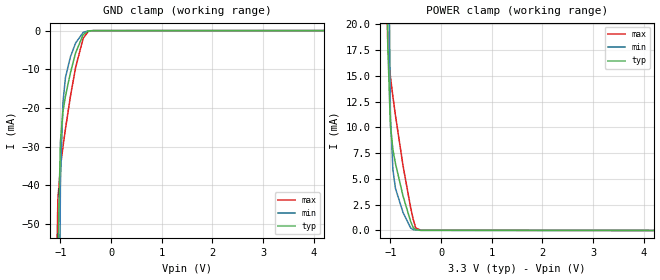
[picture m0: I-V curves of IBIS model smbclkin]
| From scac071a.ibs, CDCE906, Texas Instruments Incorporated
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[Model]   smbclkin
Model_type   Input
Polarity   Non-Inverting
Vinl   =   0.80V
Vinh   =   2.10V
|Variable   typ   min   max
C_comp   1.420e-12   1.379e-12   1.479e-12
|Variable   typ   min   max
[Voltage range]   3.3   3.0   3.6
|Variable   typ   min   max
[Temperature range]  55   110   -15
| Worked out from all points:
|   GND clamp passes 1 mA (typ) near -0.55 V on its own axis
|   POWER clamp passes 1 mA (typ) near -0.61 V on its own axis
| Note: The Input-Buffer model contains a Pull-Up resistor of
|   3.3MOhm(typ) 5MOhm(min) and 2.6MOhm(max).
[GND_clamp]
|Volts   typ   min   max
-1.2V     -6.266A    -10.23A    -3.28A
-1.1V     -212.2mA   -514.8mA   -81.05mA
-1.05V    -58.05mA   -127.1mA   -43.66mA
-1V       -28.77mA   -39.71mA   -35.23mA
-950mV    -20.93mA   -18.55mA   -30.02mA
-900mV    -16.9mA    -12.07mA   -25.35mA
-800mV    -10.78mA   -6.697mA   -16.83mA
-700mV    -5.762mA   -3.218mA   -9.538mA
-550mV    -1.018mA   -463.9uA   -1.988mA
-450mV    -128.8uA   -64.99uA   -225.9uA
-350mV    -10.79uA   -7.496uA   -11.25uA
4.2V      0A         0A         0A
[POWER_clamp]
|Volts   typ   min   max
-1.2V     1.548A     2.521A     817mA
-1.1V     56.08mA    128.7mA    27.63mA
-1.05V    17.72mA    32.97mA    17.69mA
-1V       10.13mA    11.26mA    14.91mA
-950mV    7.835mA    5.858mA    12.95mA
-900mV    6.489mA    4.073mA    11.15mA
-750mV    3.331mA    1.735mA    6.254mA
-600mV    863.1uA    238.3uA    2.196mA
-550mV    283.2uA    80.03uA    1.087mA
-500mV    77.28uA    41.59uA    235.6uA
-400mV    14.29uA    7.388uA    24.16uA
4.2V      -1.164uA   -844.8nA   -1.471uA
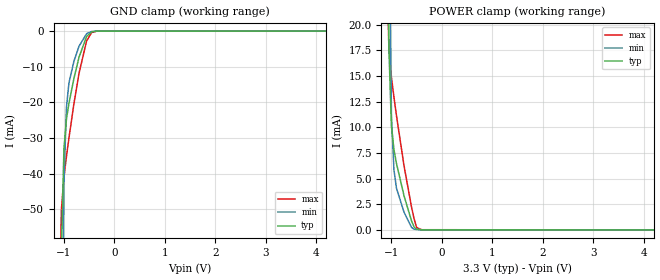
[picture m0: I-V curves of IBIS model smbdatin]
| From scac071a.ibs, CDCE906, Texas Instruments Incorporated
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|   Model   smbdatin
[Model]   smbdatin
Model_type   Input
Polarity   Non-Inverting
Vinl   =   0.80V
Vinh   =   2.10V
|Variable   typ   min   max
C_comp   1.784e-12   1.741e-12   1.846e-12
|Variable   typ   min   max
[Voltage range]   3.3   3.0   3.6
|Variable   typ   min   max
[Temperature range]  55   110   -15
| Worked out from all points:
|   GND clamp passes 1 mA (typ) near -0.52 V on its own axis
|   POWER clamp passes 1 mA (typ) near -0.61 V on its own axis
| Note: The Input-Buffer model contains a Pull-Up resistor of
|   3.3MOhm(typ) 5MOhm(min) and 2.6MOhm(max).
[GND_clamp]
|Volts   typ   min   max
-1.2V     -6.272A    -10.23A    -3.288A
-1.1V     -217.5mA   -518.9mA   -88.16mA
-1.05V    -62.86mA   -130.7mA   -50.14mA
-1V       -33.09mA   -42.94mA   -41.08mA
-950mV    -24.76mA   -21.38mA   -35.25mA
-900mV    -20.25mA   -14.51mA   -29.96mA
-800mV    -13.19mA   -8.395mA   -20.23mA
-700mV    -7.307mA   -4.239mA   -11.8mA
-550mV    -1.49mA    -725.2uA   -2.76mA
-450mV    -223.7uA   -114.6uA   -384.2uA
-350mV    -19.09uA   -13.02uA   -20.08uA
4.2V      0A         0A         0A
[POWER_clamp]
|Volts   typ   min   max
-1.2V     1.548A     2.521A     817mA
-1.1V     56.08mA    128.7mA    27.63mA
-1.05V    17.72mA    32.97mA    17.69mA
-1V       10.13mA    11.26mA    14.91mA
-950mV    7.835mA    5.858mA    12.95mA
-900mV    6.489mA    4.073mA    11.15mA
-750mV    3.331mA    1.735mA    6.254mA
-600mV    863.1uA    238.3uA    2.196mA
-550mV    283.2uA    80.03uA    1.087mA
-500mV    77.28uA    41.59uA    235.6uA
-400mV    14.29uA    7.389uA    24.16uA
4.2V      -1.164uA   -844.8nA   -1.471uA
